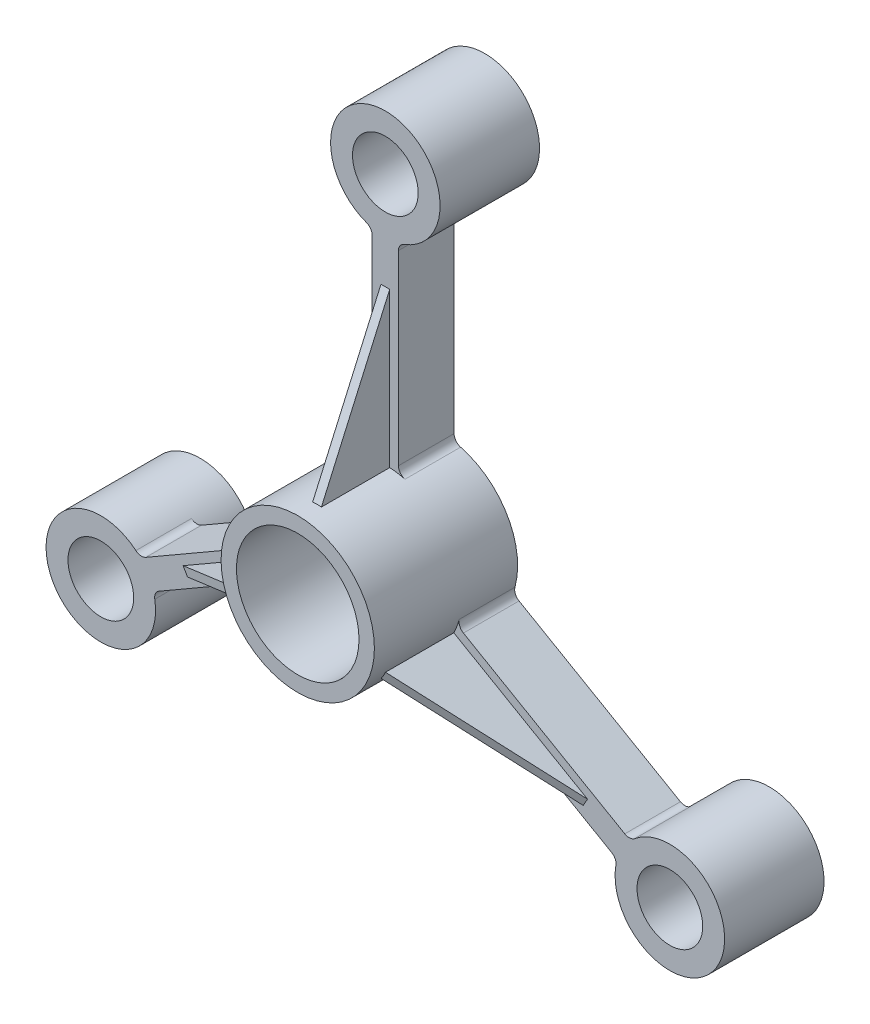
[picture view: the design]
ISO-10303-21;
HEADER;
FILE_DESCRIPTION(('STEP AP214'),'2;1');
FILE_NAME('part.step','',(''),(''),'','','');
FILE_SCHEMA(('AUTOMOTIVE_DESIGN { 1 0 10303 214 1 1 1 1 }'));
ENDSEC;
DATA;
#1=APPLICATION_CONTEXT('core data for automotive mechanical design processes');
#2=APPLICATION_PROTOCOL_DEFINITION('international standard','automotive_design',2000,#1);
#3=PRODUCT_CONTEXT('',#1,'mechanical');
#4=PRODUCT('Part','Part','',(#3));
#5=PRODUCT_RELATED_PRODUCT_CATEGORY('part','',(#4));
#6=PRODUCT_DEFINITION_FORMATION('','',#4);
#7=PRODUCT_DEFINITION_CONTEXT('part definition',#1,'design');
#8=PRODUCT_DEFINITION('design','',#6,#7);
#9=PRODUCT_DEFINITION_SHAPE('','',#8);
#10=(LENGTH_UNIT() NAMED_UNIT(*) SI_UNIT(.MILLI.,.METRE.));
#11=(NAMED_UNIT(*) PLANE_ANGLE_UNIT() SI_UNIT($,.RADIAN.));
#12=(NAMED_UNIT(*) SI_UNIT($,.STERADIAN.) SOLID_ANGLE_UNIT());
#13=UNCERTAINTY_MEASURE_WITH_UNIT(LENGTH_MEASURE(1.E-05),#10,'distance_accuracy_value','');
#14=(GEOMETRIC_REPRESENTATION_CONTEXT(3) GLOBAL_UNCERTAINTY_ASSIGNED_CONTEXT((#13)) GLOBAL_UNIT_ASSIGNED_CONTEXT((#10,
#11,#12)) REPRESENTATION_CONTEXT('',''));
#15=CARTESIAN_POINT('',(0.,0.,0.));
#16=DIRECTION('',(0.,0.,1.));
#17=DIRECTION('',(1.,0.,0.));
#18=AXIS2_PLACEMENT_3D('',#15,#16,#17);
#19=CARTESIAN_POINT('',(5.00000000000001,18.8480768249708,12.7));
#20=DIRECTION('',(0.,0.,1.));
#21=DIRECTION('',(1.,0.,0.));
#22=AXIS2_PLACEMENT_3D('',#19,#20,#21);
#23=PLANE('',#22);
#24=DIRECTION('',(0.,1.,0.));
#25=VECTOR('',#24,1.);
#26=CARTESIAN_POINT('',(1.,18.8480768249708,12.7));
#27=LINE('',#26,#25);
#28=CARTESIAN_POINT('',(1.,17.4714052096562,12.7));
#29=VERTEX_POINT('',#28);
#30=CARTESIAN_POINT('',(1.,52.7236804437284,12.7));
#31=VERTEX_POINT('',#30);
#32=EDGE_CURVE('E306',#29,#31,#27,.T.);
#33=ORIENTED_EDGE('',*,*,#32,.F.);
#34=CARTESIAN_POINT('',(0.,0.,12.7));
#35=DIRECTION('',(0.,0.,1.));
#36=DIRECTION('',(1.,0.,0.));
#37=AXIS2_PLACEMENT_3D('',#34,#35,#36);
#38=CIRCLE('',#37,17.4999999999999);
#39=CARTESIAN_POINT('',(4.48717948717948,16.9149407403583,12.7));
#40=VERTEX_POINT('',#39);
#41=EDGE_CURVE('E349',#40,#29,#38,.T.);
#42=ORIENTED_EDGE('',*,*,#41,.F.);
#43=CARTESIAN_POINT('',(5.00000000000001,18.8480768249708,12.7));
#44=DIRECTION('',(0.,0.,1.));
#45=DIRECTION('',(1.,0.,0.));
#46=AXIS2_PLACEMENT_3D('',#43,#44,#45);
#47=CIRCLE('',#46,2.);
#48=CARTESIAN_POINT('',(3.00000000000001,18.8480768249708,12.7));
#49=VERTEX_POINT('',#48);
#50=EDGE_CURVE('E359',#49,#40,#47,.T.);
#51=ORIENTED_EDGE('',*,*,#50,.F.);
#52=DIRECTION('',(0.,-1.,0.));
#53=VECTOR('',#52,1.);
#54=CARTESIAN_POINT('',(3.,61.3893424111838,12.7));
#55=LINE('',#54,#53);
#56=CARTESIAN_POINT('',(3.,61.3893424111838,12.7));
#57=VERTEX_POINT('',#56);
#58=EDGE_CURVE('E483',#57,#49,#55,.T.);
#59=ORIENTED_EDGE('',*,*,#58,.F.);
#60=CARTESIAN_POINT('',(5.,61.3893424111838,12.7));
#61=DIRECTION('',(0.,0.,1.));
#62=DIRECTION('',(1.,0.,0.));
#63=AXIS2_PLACEMENT_3D('',#60,#61,#62);
#64=CIRCLE('',#63,2.);
#65=CARTESIAN_POINT('',(4.31034482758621,63.2666744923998,12.7));
#66=VERTEX_POINT('',#65);
#67=EDGE_CURVE('E480',#66,#57,#64,.T.);
#68=ORIENTED_EDGE('',*,*,#67,.F.);
#69=CARTESIAN_POINT('',(0.,75.,12.7));
#70=DIRECTION('',(0.,0.,1.));
#71=DIRECTION('',(1.,0.,0.));
#72=AXIS2_PLACEMENT_3D('',#69,#70,#71);
#73=CIRCLE('',#72,12.5);
#74=CARTESIAN_POINT('',(-4.31034482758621,63.2666744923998,12.7));
#75=VERTEX_POINT('',#74);
#76=EDGE_CURVE('E478',#66,#75,#73,.T.);
#77=ORIENTED_EDGE('',*,*,#76,.T.);
#78=CARTESIAN_POINT('',(-5.,61.3893424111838,12.7));
#79=DIRECTION('',(0.,0.,1.));
#80=DIRECTION('',(1.,0.,0.));
#81=AXIS2_PLACEMENT_3D('',#78,#79,#80);
#82=CIRCLE('',#81,1.99999999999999);
#83=CARTESIAN_POINT('',(-3.00000000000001,61.3893424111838,12.7));
#84=VERTEX_POINT('',#83);
#85=EDGE_CURVE('E474',#84,#75,#82,.T.);
#86=ORIENTED_EDGE('',*,*,#85,.F.);
#87=DIRECTION('',(0.,-1.,0.));
#88=VECTOR('',#87,1.);
#89=CARTESIAN_POINT('',(-3.,61.3893424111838,12.7));
#90=LINE('',#89,#88);
#91=CARTESIAN_POINT('',(-3.,18.8480768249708,12.7));
#92=VERTEX_POINT('',#91);
#93=EDGE_CURVE('E472',#84,#92,#90,.T.);
#94=ORIENTED_EDGE('',*,*,#93,.T.);
#95=CARTESIAN_POINT('',(-5.,18.8480768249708,12.7));
#96=DIRECTION('',(0.,0.,1.));
#97=DIRECTION('',(1.,0.,0.));
#98=AXIS2_PLACEMENT_3D('',#95,#96,#97);
#99=CIRCLE('',#98,2.);
#100=CARTESIAN_POINT('',(-4.48717948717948,16.9149407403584,12.7));
#101=VERTEX_POINT('',#100);
#102=EDGE_CURVE('E475',#101,#92,#99,.T.);
#103=ORIENTED_EDGE('',*,*,#102,.F.);
#104=CARTESIAN_POINT('',(-1.,17.4714052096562,12.7));
#105=VERTEX_POINT('',#104);
#106=EDGE_CURVE('E342',#105,#101,#38,.T.);
#107=ORIENTED_EDGE('',*,*,#106,.F.);
#108=DIRECTION('',(0.,1.,0.));
#109=VECTOR('',#108,1.);
#110=CARTESIAN_POINT('',(-1.,18.8480768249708,12.7));
#111=LINE('',#110,#109);
#112=CARTESIAN_POINT('',(-1.,52.7236804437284,12.7));
#113=VERTEX_POINT('',#112);
#114=EDGE_CURVE('E302',#105,#113,#111,.T.);
#115=ORIENTED_EDGE('',*,*,#114,.T.);
#116=DIRECTION('',(-1.,0.,0.));
#117=VECTOR('',#116,1.);
#118=CARTESIAN_POINT('',(5.00000000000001,52.7236804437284,12.7));
#119=LINE('',#118,#117);
#120=EDGE_CURVE('E311',#31,#113,#119,.T.);
#121=ORIENTED_EDGE('',*,*,#120,.F.);
#122=EDGE_LOOP('',(#33,#42,#51,#59,#68,#77,#86,#94,#103,#107,#115,#121));
#123=FACE_BOUND('',#122,.T.);
#124=CARTESIAN_POINT('',(0.,75.,12.7));
#125=DIRECTION('',(0.,0.,1.));
#126=DIRECTION('',(1.,0.,0.));
#127=AXIS2_PLACEMENT_3D('',#124,#125,#126);
#128=CIRCLE('',#127,7.5);
#129=CARTESIAN_POINT('',(7.5,75.,12.7));
#130=VERTEX_POINT('',#129);
#131=EDGE_CURVE('E324',#130,#130,#128,.T.);
#132=ORIENTED_EDGE('',*,*,#131,.F.);
#133=EDGE_LOOP('',(#132));
#134=FACE_BOUND('',#133,.T.);
#135=ADVANCED_FACE('F32',(#123,#134),#23,.T.);
#136=DIRECTION('',(-0.866025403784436,-0.500000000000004,0.));
#137=VECTOR('',#136,1.);
#138=CARTESIAN_POINT('',(11.4114566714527,7.74310811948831,12.7));
#139=LINE('',#138,#137);
#140=CARTESIAN_POINT('',(-15.630680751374,-7.86967720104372,12.7));
#141=VERTEX_POINT('',#140);
#142=CARTESIAN_POINT('',(-46.1600466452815,-25.49581481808,12.7));
#143=VERTEX_POINT('',#142);
#144=EDGE_CURVE('E288',#141,#143,#139,.T.);
#145=ORIENTED_EDGE('',*,*,#144,.F.);
#146=CARTESIAN_POINT('',(-16.8923581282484,-4.57145894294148,12.7));
#147=VERTEX_POINT('',#146);
#148=EDGE_CURVE('E11',#147,#141,#38,.T.);
#149=ORIENTED_EDGE('',*,*,#148,.F.);
#150=CARTESIAN_POINT('',(-18.8229133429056,-5.09391139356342,12.7));
#151=DIRECTION('',(0.,0.,1.));
#152=DIRECTION('',(1.,0.,0.));
#153=AXIS2_PLACEMENT_3D('',#150,#151,#152);
#154=CIRCLE('',#153,2.00000000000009);
#155=CARTESIAN_POINT('',(-17.8229133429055,-6.82596220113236,12.7));
#156=VERTEX_POINT('',#155);
#157=EDGE_CURVE('E471',#156,#147,#154,.T.);
#158=ORIENTED_EDGE('',*,*,#157,.F.);
#159=DIRECTION('',(0.866025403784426,0.500000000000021,0.));
#160=VECTOR('',#159,1.);
#161=CARTESIAN_POINT('',(-54.6647300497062,-28.0965949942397,12.7));
#162=LINE('',#161,#160);
#163=CARTESIAN_POINT('',(-54.6647300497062,-28.0965949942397,12.7));
#164=VERTEX_POINT('',#163);
#165=EDGE_CURVE('E468',#164,#156,#162,.T.);
#166=ORIENTED_EDGE('',*,*,#165,.F.);
#167=CARTESIAN_POINT('',(-55.6647300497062,-26.3645441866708,12.7));
#168=DIRECTION('',(0.,0.,1.));
#169=DIRECTION('',(1.,0.,0.));
#170=AXIS2_PLACEMENT_3D('',#167,#168,#169);
#171=CIRCLE('',#170,2.);
#172=CARTESIAN_POINT('',(-56.9457197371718,-27.9004691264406,12.7));
#173=VERTEX_POINT('',#172);
#174=EDGE_CURVE('E465',#173,#164,#171,.T.);
#175=ORIENTED_EDGE('',*,*,#174,.F.);
#176=CARTESIAN_POINT('',(-64.951905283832,-37.5000000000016,12.7));
#177=DIRECTION('',(0.,0.,1.));
#178=DIRECTION('',(1.,0.,0.));
#179=AXIS2_PLACEMENT_3D('',#176,#177,#178);
#180=CIRCLE('',#179,12.5);
#181=CARTESIAN_POINT('',(-52.6353749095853,-35.3662053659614,12.7));
#182=VERTEX_POINT('',#181);
#183=EDGE_CURVE('E463',#173,#182,#180,.T.);
#184=ORIENTED_EDGE('',*,*,#183,.T.);
#185=CARTESIAN_POINT('',(-50.6647300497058,-35.024798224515,12.7));
#186=DIRECTION('',(0.,0.,-1.));
#187=DIRECTION('',(-1.,0.,0.));
#188=AXIS2_PLACEMENT_3D('',#185,#186,#187);
#189=CIRCLE('',#188,2.);
#190=CARTESIAN_POINT('',(-51.6647300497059,-33.2927474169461,12.7));
#191=VERTEX_POINT('',#190);
#192=EDGE_CURVE('E460',#182,#191,#189,.T.);
#193=ORIENTED_EDGE('',*,*,#192,.T.);
#194=DIRECTION('',(0.866025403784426,0.500000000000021,0.));
#195=VECTOR('',#194,1.);
#196=CARTESIAN_POINT('',(-51.6647300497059,-33.2927474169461,12.7));
#197=LINE('',#196,#195);
#198=CARTESIAN_POINT('',(-14.8229133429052,-12.0221146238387,12.7));
#199=VERTEX_POINT('',#198);
#200=EDGE_CURVE('E458',#191,#199,#197,.T.);
#201=ORIENTED_EDGE('',*,*,#200,.T.);
#202=CARTESIAN_POINT('',(-13.8229133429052,-13.7541654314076,12.7));
#203=DIRECTION('',(0.,0.,-1.));
#204=DIRECTION('',(-1.,0.,0.));
#205=AXIS2_PLACEMENT_3D('',#202,#203,#204);
#206=CIRCLE('',#205,1.99999999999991);
#207=CARTESIAN_POINT('',(-12.4051786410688,-12.3434817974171,12.7));
#208=VERTEX_POINT('',#207);
#209=EDGE_CURVE('E461',#199,#208,#206,.T.);
#210=ORIENTED_EDGE('',*,*,#209,.T.);
#211=CARTESIAN_POINT('',(-14.630680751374,-9.60172800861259,12.7));
#212=VERTEX_POINT('',#211);
#213=EDGE_CURVE('E42',#212,#208,#38,.T.);
#214=ORIENTED_EDGE('',*,*,#213,.F.);
#215=DIRECTION('',(-0.866025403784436,-0.500000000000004,0.));
#216=VECTOR('',#215,1.);
#217=CARTESIAN_POINT('',(12.4114566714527,6.01105731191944,12.7));
#218=LINE('',#217,#216);
#219=CARTESIAN_POINT('',(-45.1600466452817,-27.227865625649,12.6999999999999));
#220=VERTEX_POINT('',#219);
#221=EDGE_CURVE('E284',#212,#220,#218,.T.);
#222=ORIENTED_EDGE('',*,*,#221,.T.);
#223=DIRECTION('',(0.500000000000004,-0.866025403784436,0.));
#224=VECTOR('',#223,1.);
#225=CARTESIAN_POINT('',(-52.5715033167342,-14.3908461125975,12.7));
#226=LINE('',#225,#224);
#227=EDGE_CURVE('E58',#143,#220,#226,.T.);
#228=ORIENTED_EDGE('',*,*,#227,.F.);
#229=EDGE_LOOP('',(#145,#149,#158,#166,#175,#184,#193,#201,#210,#214,#222,#228));
#230=FACE_BOUND('',#229,.T.);
#231=CARTESIAN_POINT('',(-64.951905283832,-37.5000000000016,12.7));
#232=DIRECTION('',(0.,0.,1.));
#233=DIRECTION('',(1.,0.,0.));
#234=AXIS2_PLACEMENT_3D('',#231,#232,#233);
#235=CIRCLE('',#234,7.5);
#236=CARTESIAN_POINT('',(-57.451905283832,-37.5000000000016,12.7));
#237=VERTEX_POINT('',#236);
#238=EDGE_CURVE('E318',#237,#237,#235,.T.);
#239=ORIENTED_EDGE('',*,*,#238,.F.);
#240=EDGE_LOOP('',(#239));
#241=FACE_BOUND('',#240,.T.);
#242=ADVANCED_FACE('F624',(#230,#241),#23,.T.);
#243=CARTESIAN_POINT('',(5.00000000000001,18.8480768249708,0.));
#244=DIRECTION('',(0.,0.,1.));
#245=DIRECTION('',(1.,0.,0.));
#246=AXIS2_PLACEMENT_3D('',#243,#244,#245);
#247=PLANE('',#246);
#248=CARTESIAN_POINT('',(0.,0.,0.));
#249=DIRECTION('',(0.,0.,1.));
#250=DIRECTION('',(1.,0.,0.));
#251=AXIS2_PLACEMENT_3D('',#248,#249,#250);
#252=CIRCLE('',#251,8.33292396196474);
#253=CARTESIAN_POINT('',(8.33292396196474,0.,0.));
#254=VERTEX_POINT('',#253);
#255=EDGE_CURVE('E335',#254,#254,#252,.T.);
#256=ORIENTED_EDGE('',*,*,#255,.T.);
#257=EDGE_LOOP('',(#256));
#258=FACE_BOUND('',#257,.T.);
#259=CARTESIAN_POINT('',(-18.8229133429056,-5.09391139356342,0.));
#260=DIRECTION('',(0.,0.,1.));
#261=DIRECTION('',(1.,0.,0.));
#262=AXIS2_PLACEMENT_3D('',#259,#260,#261);
#263=CIRCLE('',#262,2.00000000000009);
#264=CARTESIAN_POINT('',(-17.8229133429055,-6.82596220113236,0.));
#265=VERTEX_POINT('',#264);
#266=CARTESIAN_POINT('',(-16.8923581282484,-4.57145894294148,0.));
#267=VERTEX_POINT('',#266);
#268=EDGE_CURVE('E522',#265,#267,#263,.T.);
#269=ORIENTED_EDGE('',*,*,#268,.T.);
#270=CARTESIAN_POINT('',(0.,0.,0.));
#271=DIRECTION('',(0.,0.,1.));
#272=DIRECTION('',(1.,0.,0.));
#273=AXIS2_PLACEMENT_3D('',#270,#271,#272);
#274=CIRCLE('',#273,17.5);
#275=CARTESIAN_POINT('',(-4.48717948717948,16.9149407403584,0.));
#276=VERTEX_POINT('',#275);
#277=EDGE_CURVE('E525',#276,#267,#274,.T.);
#278=ORIENTED_EDGE('',*,*,#277,.F.);
#279=CARTESIAN_POINT('',(-5.,18.8480768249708,0.));
#280=DIRECTION('',(0.,0.,1.));
#281=DIRECTION('',(1.,0.,0.));
#282=AXIS2_PLACEMENT_3D('',#279,#280,#281);
#283=CIRCLE('',#282,2.);
#284=CARTESIAN_POINT('',(-3.,18.8480768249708,0.));
#285=VERTEX_POINT('',#284);
#286=EDGE_CURVE('E527',#276,#285,#283,.T.);
#287=ORIENTED_EDGE('',*,*,#286,.T.);
#288=DIRECTION('',(0.,-1.,0.));
#289=VECTOR('',#288,1.);
#290=CARTESIAN_POINT('',(-3.,61.3893424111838,0.));
#291=LINE('',#290,#289);
#292=CARTESIAN_POINT('',(-3.00000000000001,61.3893424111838,0.));
#293=VERTEX_POINT('',#292);
#294=EDGE_CURVE('E529',#293,#285,#291,.T.);
#295=ORIENTED_EDGE('',*,*,#294,.F.);
#296=CARTESIAN_POINT('',(-5.,61.3893424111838,0.));
#297=DIRECTION('',(0.,0.,1.));
#298=DIRECTION('',(1.,0.,0.));
#299=AXIS2_PLACEMENT_3D('',#296,#297,#298);
#300=CIRCLE('',#299,1.99999999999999);
#301=CARTESIAN_POINT('',(-4.31034482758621,63.2666744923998,0.));
#302=VERTEX_POINT('',#301);
#303=EDGE_CURVE('E531',#293,#302,#300,.T.);
#304=ORIENTED_EDGE('',*,*,#303,.T.);
#305=CARTESIAN_POINT('',(0.,75.,0.));
#306=DIRECTION('',(0.,0.,-1.));
#307=DIRECTION('',(-1.,0.,0.));
#308=AXIS2_PLACEMENT_3D('',#305,#306,#307);
#309=CIRCLE('',#308,12.5);
#310=CARTESIAN_POINT('',(4.3103448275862,63.2666744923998,0.));
#311=VERTEX_POINT('',#310);
#312=EDGE_CURVE('E437',#311,#302,#309,.T.);
#313=ORIENTED_EDGE('',*,*,#312,.F.);
#314=CARTESIAN_POINT('',(5.,61.3893424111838,0.));
#315=DIRECTION('',(0.,0.,1.));
#316=DIRECTION('',(1.,0.,0.));
#317=AXIS2_PLACEMENT_3D('',#314,#315,#316);
#318=CIRCLE('',#317,2.);
#319=CARTESIAN_POINT('',(3.,61.3893424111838,0.));
#320=VERTEX_POINT('',#319);
#321=EDGE_CURVE('E536',#311,#320,#318,.T.);
#322=ORIENTED_EDGE('',*,*,#321,.T.);
#323=DIRECTION('',(0.,-1.,0.));
#324=VECTOR('',#323,1.);
#325=CARTESIAN_POINT('',(3.,61.3893424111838,0.));
#326=LINE('',#325,#324);
#327=CARTESIAN_POINT('',(3.00000000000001,18.8480768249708,0.));
#328=VERTEX_POINT('',#327);
#329=EDGE_CURVE('E389',#320,#328,#326,.T.);
#330=ORIENTED_EDGE('',*,*,#329,.T.);
#331=CARTESIAN_POINT('',(5.00000000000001,18.8480768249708,0.));
#332=DIRECTION('',(0.,0.,1.));
#333=DIRECTION('',(1.,0.,0.));
#334=AXIS2_PLACEMENT_3D('',#331,#332,#333);
#335=CIRCLE('',#334,2.);
#336=CARTESIAN_POINT('',(4.48717948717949,16.9149407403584,0.));
#337=VERTEX_POINT('',#336);
#338=EDGE_CURVE('E486',#328,#337,#335,.T.);
#339=ORIENTED_EDGE('',*,*,#338,.T.);
#340=CARTESIAN_POINT('',(0.,0.,0.));
#341=DIRECTION('',(0.,0.,1.));
#342=DIRECTION('',(1.,0.,0.));
#343=AXIS2_PLACEMENT_3D('',#340,#341,#342);
#344=CIRCLE('',#343,17.5);
#345=CARTESIAN_POINT('',(16.8923581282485,-4.57145894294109,0.));
#346=VERTEX_POINT('',#345);
#347=EDGE_CURVE('E489',#346,#337,#344,.T.);
#348=ORIENTED_EDGE('',*,*,#347,.F.);
#349=CARTESIAN_POINT('',(18.8229133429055,-5.09391139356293,0.));
#350=DIRECTION('',(0.,0.,1.));
#351=DIRECTION('',(1.,0.,0.));
#352=AXIS2_PLACEMENT_3D('',#349,#350,#351);
#353=CIRCLE('',#352,2.);
#354=CARTESIAN_POINT('',(17.8229133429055,-6.82596220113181,0.));
#355=VERTEX_POINT('',#354);
#356=EDGE_CURVE('E491',#346,#355,#353,.T.);
#357=ORIENTED_EDGE('',*,*,#356,.T.);
#358=DIRECTION('',(0.866025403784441,-0.499999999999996,0.));
#359=VECTOR('',#358,1.);
#360=CARTESIAN_POINT('',(17.8229133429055,-6.82596220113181,0.));
#361=LINE('',#360,#359);
#362=CARTESIAN_POINT('',(54.6647300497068,-28.0965949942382,0.));
#363=VERTEX_POINT('',#362);
#364=EDGE_CURVE('E494',#355,#363,#361,.T.);
#365=ORIENTED_EDGE('',*,*,#364,.T.);
#366=CARTESIAN_POINT('',(55.6647300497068,-26.3645441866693,0.));
#367=DIRECTION('',(0.,0.,1.));
#368=DIRECTION('',(1.,0.,0.));
#369=AXIS2_PLACEMENT_3D('',#366,#367,#368);
#370=CIRCLE('',#369,2.00000000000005);
#371=CARTESIAN_POINT('',(56.9457197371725,-27.9004691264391,0.));
#372=VERTEX_POINT('',#371);
#373=EDGE_CURVE('E497',#363,#372,#370,.T.);
#374=ORIENTED_EDGE('',*,*,#373,.T.);
#375=CARTESIAN_POINT('',(64.9519052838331,-37.4999999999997,0.));
#376=DIRECTION('',(0.,0.,-1.));
#377=DIRECTION('',(-1.,0.,0.));
#378=AXIS2_PLACEMENT_3D('',#375,#376,#377);
#379=CIRCLE('',#378,12.5);
#380=CARTESIAN_POINT('',(52.6353749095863,-35.3662053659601,0.));
#381=VERTEX_POINT('',#380);
#382=EDGE_CURVE('E696',#381,#372,#379,.T.);
#383=ORIENTED_EDGE('',*,*,#382,.F.);
#384=CARTESIAN_POINT('',(50.6647300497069,-35.0247982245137,0.));
#385=DIRECTION('',(0.,0.,1.));
#386=DIRECTION('',(1.,0.,0.));
#387=AXIS2_PLACEMENT_3D('',#384,#385,#386);
#388=CIRCLE('',#387,1.99999999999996);
#389=CARTESIAN_POINT('',(51.6647300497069,-33.2927474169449,0.));
#390=VERTEX_POINT('',#389);
#391=EDGE_CURVE('E500',#381,#390,#388,.T.);
#392=ORIENTED_EDGE('',*,*,#391,.T.);
#393=DIRECTION('',(0.866025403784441,-0.499999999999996,0.));
#394=VECTOR('',#393,1.);
#395=CARTESIAN_POINT('',(14.8229133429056,-12.0221146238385,0.));
#396=LINE('',#395,#394);
#397=CARTESIAN_POINT('',(14.8229133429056,-12.0221146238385,0.));
#398=VERTEX_POINT('',#397);
#399=EDGE_CURVE('E503',#398,#390,#396,.T.);
#400=ORIENTED_EDGE('',*,*,#399,.F.);
#401=CARTESIAN_POINT('',(13.8229133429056,-13.7541654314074,0.));
#402=DIRECTION('',(0.,0.,-1.));
#403=DIRECTION('',(-1.,0.,0.));
#404=AXIS2_PLACEMENT_3D('',#401,#402,#403);
#405=CIRCLE('',#404,2.);
#406=CARTESIAN_POINT('',(12.4051786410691,-12.3434817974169,0.));
#407=VERTEX_POINT('',#406);
#408=EDGE_CURVE('E506',#407,#398,#405,.T.);
#409=ORIENTED_EDGE('',*,*,#408,.F.);
#410=CARTESIAN_POINT('',(0.,0.,0.));
#411=DIRECTION('',(0.,0.,1.));
#412=DIRECTION('',(1.,0.,0.));
#413=AXIS2_PLACEMENT_3D('',#410,#411,#412);
#414=CIRCLE('',#413,17.5);
#415=CARTESIAN_POINT('',(-12.4051786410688,-12.3434817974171,0.));
#416=VERTEX_POINT('',#415);
#417=EDGE_CURVE('E508',#416,#407,#414,.T.);
#418=ORIENTED_EDGE('',*,*,#417,.F.);
#419=CARTESIAN_POINT('',(-13.8229133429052,-13.7541654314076,0.));
#420=DIRECTION('',(0.,0.,-1.));
#421=DIRECTION('',(-1.,0.,0.));
#422=AXIS2_PLACEMENT_3D('',#419,#420,#421);
#423=CIRCLE('',#422,1.99999999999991);
#424=CARTESIAN_POINT('',(-14.8229133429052,-12.0221146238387,0.));
#425=VERTEX_POINT('',#424);
#426=EDGE_CURVE('E510',#425,#416,#423,.T.);
#427=ORIENTED_EDGE('',*,*,#426,.F.);
#428=DIRECTION('',(0.866025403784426,0.500000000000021,0.));
#429=VECTOR('',#428,1.);
#430=CARTESIAN_POINT('',(-51.6647300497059,-33.2927474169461,0.));
#431=LINE('',#430,#429);
#432=CARTESIAN_POINT('',(-51.6647300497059,-33.2927474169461,0.));
#433=VERTEX_POINT('',#432);
#434=EDGE_CURVE('E512',#433,#425,#431,.T.);
#435=ORIENTED_EDGE('',*,*,#434,.F.);
#436=CARTESIAN_POINT('',(-50.6647300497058,-35.024798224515,0.));
#437=DIRECTION('',(0.,0.,-1.));
#438=DIRECTION('',(-1.,0.,0.));
#439=AXIS2_PLACEMENT_3D('',#436,#437,#438);
#440=CIRCLE('',#439,2.);
#441=CARTESIAN_POINT('',(-52.6353749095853,-35.3662053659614,0.));
#442=VERTEX_POINT('',#441);
#443=EDGE_CURVE('E514',#442,#433,#440,.T.);
#444=ORIENTED_EDGE('',*,*,#443,.F.);
#445=CARTESIAN_POINT('',(-64.951905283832,-37.5000000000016,0.));
#446=DIRECTION('',(0.,0.,-1.));
#447=DIRECTION('',(-1.,0.,0.));
#448=AXIS2_PLACEMENT_3D('',#445,#446,#447);
#449=CIRCLE('',#448,12.5);
#450=CARTESIAN_POINT('',(-56.9457197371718,-27.9004691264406,0.));
#451=VERTEX_POINT('',#450);
#452=EDGE_CURVE('E348',#451,#442,#449,.T.);
#453=ORIENTED_EDGE('',*,*,#452,.F.);
#454=CARTESIAN_POINT('',(-55.6647300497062,-26.3645441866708,0.));
#455=DIRECTION('',(0.,0.,1.));
#456=DIRECTION('',(1.,0.,0.));
#457=AXIS2_PLACEMENT_3D('',#454,#455,#456);
#458=CIRCLE('',#457,2.);
#459=CARTESIAN_POINT('',(-54.6647300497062,-28.0965949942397,0.));
#460=VERTEX_POINT('',#459);
#461=EDGE_CURVE('E516',#451,#460,#458,.T.);
#462=ORIENTED_EDGE('',*,*,#461,.T.);
#463=DIRECTION('',(0.866025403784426,0.500000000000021,0.));
#464=VECTOR('',#463,1.);
#465=CARTESIAN_POINT('',(-54.6647300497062,-28.0965949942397,0.));
#466=LINE('',#465,#464);
#467=EDGE_CURVE('E519',#460,#265,#466,.T.);
#468=ORIENTED_EDGE('',*,*,#467,.T.);
#469=EDGE_LOOP('',(#269,#278,#287,#295,#304,#313,#322,#330,#339,#348,#357,#365,#374,#383,#392,
#400,#409,#418,#427,#435,#444,#453,#462,#468));
#470=FACE_BOUND('',#469,.T.);
#471=ADVANCED_FACE('F558',(#258,#470),#247,.F.);
#472=CARTESIAN_POINT('',(5.00000000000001,18.8480768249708,12.7));
#473=DIRECTION('',(0.,0.,-1.));
#474=DIRECTION('',(-1.,0.,0.));
#475=AXIS2_PLACEMENT_3D('',#472,#473,#474);
#476=CYLINDRICAL_SURFACE('',#475,2.);
#477=ORIENTED_EDGE('',*,*,#338,.F.);
#478=DIRECTION('',(0.,0.,-1.));
#479=VECTOR('',#478,1.);
#480=CARTESIAN_POINT('',(3.00000000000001,18.8480768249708,12.7));
#481=LINE('',#480,#479);
#482=EDGE_CURVE('E378',#49,#328,#481,.T.);
#483=ORIENTED_EDGE('',*,*,#482,.F.);
#484=ORIENTED_EDGE('',*,*,#50,.T.);
#485=DIRECTION('',(0.,0.,-1.));
#486=VECTOR('',#485,1.);
#487=CARTESIAN_POINT('',(4.48717948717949,16.9149407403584,12.7));
#488=LINE('',#487,#486);
#489=EDGE_CURVE('E485',#40,#337,#488,.T.);
#490=ORIENTED_EDGE('',*,*,#489,.T.);
#491=EDGE_LOOP('',(#477,#483,#484,#490));
#492=FACE_BOUND('',#491,.T.);
#493=ADVANCED_FACE('F34',(#492),#476,.F.);
#494=CARTESIAN_POINT('',(3.,61.3893424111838,12.7));
#495=DIRECTION('',(1.,0.,0.));
#496=DIRECTION('',(0.,1.,0.));
#497=AXIS2_PLACEMENT_3D('',#494,#495,#496);
#498=PLANE('',#497);
#499=ORIENTED_EDGE('',*,*,#329,.F.);
#500=DIRECTION('',(0.,0.,-1.));
#501=VECTOR('',#500,1.);
#502=CARTESIAN_POINT('',(3.,61.3893424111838,12.7));
#503=LINE('',#502,#501);
#504=EDGE_CURVE('E380',#57,#320,#503,.T.);
#505=ORIENTED_EDGE('',*,*,#504,.F.);
#506=ORIENTED_EDGE('',*,*,#58,.T.);
#507=ORIENTED_EDGE('',*,*,#482,.T.);
#508=EDGE_LOOP('',(#499,#505,#506,#507));
#509=FACE_BOUND('',#508,.T.);
#510=ADVANCED_FACE('F561',(#509),#498,.T.);
#511=CARTESIAN_POINT('',(5.,61.3893424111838,12.7));
#512=DIRECTION('',(0.,0.,-1.));
#513=DIRECTION('',(-1.,0.,0.));
#514=AXIS2_PLACEMENT_3D('',#511,#512,#513);
#515=CYLINDRICAL_SURFACE('',#514,2.);
#516=ORIENTED_EDGE('',*,*,#321,.F.);
#517=DIRECTION('',(0.,0.,-1.));
#518=VECTOR('',#517,1.);
#519=CARTESIAN_POINT('',(4.31034482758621,63.2666744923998,12.7));
#520=LINE('',#519,#518);
#521=EDGE_CURVE('E386',#66,#311,#520,.T.);
#522=ORIENTED_EDGE('',*,*,#521,.F.);
#523=ORIENTED_EDGE('',*,*,#67,.T.);
#524=ORIENTED_EDGE('',*,*,#504,.T.);
#525=EDGE_LOOP('',(#516,#522,#523,#524));
#526=FACE_BOUND('',#525,.T.);
#527=ADVANCED_FACE('F797',(#526),#515,.F.);
#528=CARTESIAN_POINT('',(0.,75.,12.7));
#529=DIRECTION('',(0.,0.,-1.));
#530=DIRECTION('',(-1.,0.,0.));
#531=AXIS2_PLACEMENT_3D('',#528,#529,#530);
#532=CYLINDRICAL_SURFACE('',#531,12.5);
#533=CARTESIAN_POINT('',(0.,75.,-10.));
#534=DIRECTION('',(0.,0.,-1.));
#535=DIRECTION('',(-1.,0.,0.));
#536=AXIS2_PLACEMENT_3D('',#533,#534,#535);
#537=CIRCLE('',#536,12.5);
#538=CARTESIAN_POINT('',(-12.5,75.,-10.));
#539=VERTEX_POINT('',#538);
#540=EDGE_CURVE('E440',#539,#539,#537,.T.);
#541=ORIENTED_EDGE('',*,*,#540,.F.);
#542=EDGE_LOOP('',(#541));
#543=FACE_BOUND('',#542,.T.);
#544=ORIENTED_EDGE('',*,*,#312,.T.);
#545=DIRECTION('',(0.,0.,-1.));
#546=VECTOR('',#545,1.);
#547=CARTESIAN_POINT('',(-4.31034482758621,63.2666744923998,12.7));
#548=LINE('',#547,#546);
#549=EDGE_CURVE('E394',#75,#302,#548,.T.);
#550=ORIENTED_EDGE('',*,*,#549,.F.);
#551=ORIENTED_EDGE('',*,*,#76,.F.);
#552=ORIENTED_EDGE('',*,*,#521,.T.);
#553=EDGE_LOOP('',(#544,#550,#551,#552));
#554=FACE_BOUND('',#553,.T.);
#555=ADVANCED_FACE('F556',(#543,#554),#532,.T.);
#556=CARTESIAN_POINT('',(-5.,61.3893424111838,12.7));
#557=DIRECTION('',(0.,0.,-1.));
#558=DIRECTION('',(-1.,0.,0.));
#559=AXIS2_PLACEMENT_3D('',#556,#557,#558);
#560=CYLINDRICAL_SURFACE('',#559,1.99999999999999);
#561=ORIENTED_EDGE('',*,*,#303,.F.);
#562=DIRECTION('',(0.,0.,-1.));
#563=VECTOR('',#562,1.);
#564=CARTESIAN_POINT('',(-3.00000000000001,61.3893424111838,12.7));
#565=LINE('',#564,#563);
#566=EDGE_CURVE('E392',#84,#293,#565,.T.);
#567=ORIENTED_EDGE('',*,*,#566,.F.);
#568=ORIENTED_EDGE('',*,*,#85,.T.);
#569=ORIENTED_EDGE('',*,*,#549,.T.);
#570=EDGE_LOOP('',(#561,#567,#568,#569));
#571=FACE_BOUND('',#570,.T.);
#572=ADVANCED_FACE('F554',(#571),#560,.F.);
#573=CARTESIAN_POINT('',(-3.,61.3893424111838,12.7));
#574=DIRECTION('',(1.,0.,0.));
#575=DIRECTION('',(0.,1.,0.));
#576=AXIS2_PLACEMENT_3D('',#573,#574,#575);
#577=PLANE('',#576);
#578=ORIENTED_EDGE('',*,*,#294,.T.);
#579=DIRECTION('',(0.,0.,-1.));
#580=VECTOR('',#579,1.);
#581=CARTESIAN_POINT('',(-3.,18.8480768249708,12.7));
#582=LINE('',#581,#580);
#583=EDGE_CURVE('E395',#92,#285,#582,.T.);
#584=ORIENTED_EDGE('',*,*,#583,.F.);
#585=ORIENTED_EDGE('',*,*,#93,.F.);
#586=ORIENTED_EDGE('',*,*,#566,.T.);
#587=EDGE_LOOP('',(#578,#584,#585,#586));
#588=FACE_BOUND('',#587,.T.);
#589=ADVANCED_FACE('F614',(#588),#577,.F.);
#590=CARTESIAN_POINT('',(-5.,18.8480768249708,12.7));
#591=DIRECTION('',(0.,0.,-1.));
#592=DIRECTION('',(-1.,0.,0.));
#593=AXIS2_PLACEMENT_3D('',#590,#591,#592);
#594=CYLINDRICAL_SURFACE('',#593,2.);
#595=ORIENTED_EDGE('',*,*,#286,.F.);
#596=DIRECTION('',(0.,0.,-1.));
#597=VECTOR('',#596,1.);
#598=CARTESIAN_POINT('',(-4.48717948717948,16.9149407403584,12.7));
#599=LINE('',#598,#597);
#600=EDGE_CURVE('E397',#101,#276,#599,.T.);
#601=ORIENTED_EDGE('',*,*,#600,.F.);
#602=ORIENTED_EDGE('',*,*,#102,.T.);
#603=ORIENTED_EDGE('',*,*,#583,.T.);
#604=EDGE_LOOP('',(#595,#601,#602,#603));
#605=FACE_BOUND('',#604,.T.);
#606=ADVANCED_FACE('F608',(#605),#594,.F.);
#607=CARTESIAN_POINT('',(0.,0.,12.7));
#608=DIRECTION('',(0.,0.,-1.));
#609=DIRECTION('',(-1.,0.,0.));
#610=AXIS2_PLACEMENT_3D('',#607,#608,#609);
#611=CYLINDRICAL_SURFACE('',#610,17.5);
#612=ORIENTED_EDGE('',*,*,#277,.T.);
#613=DIRECTION('',(0.,0.,-1.));
#614=VECTOR('',#613,1.);
#615=CARTESIAN_POINT('',(-16.8923581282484,-4.57145894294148,12.7));
#616=LINE('',#615,#614);
#617=EDGE_CURVE('E400',#147,#267,#616,.T.);
#618=ORIENTED_EDGE('',*,*,#617,.F.);
#619=ORIENTED_EDGE('',*,*,#148,.T.);
#620=DIRECTION('',(0.,0.,-1.));
#621=VECTOR('',#620,1.);
#622=CARTESIAN_POINT('',(-15.630680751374,-7.86967720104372,12.7));
#623=LINE('',#622,#621);
#624=CARTESIAN_POINT('',(-15.630680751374,-7.86967720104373,28.2923525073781));
#625=VERTEX_POINT('',#624);
#626=EDGE_CURVE('E286',#141,#625,#623,.F.);
#627=ORIENTED_EDGE('',*,*,#626,.T.);
#628=CARTESIAN_POINT('',(0.,0.,36.0200894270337));
#629=DIRECTION('',(-0.350312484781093,-0.202253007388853,0.914535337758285));
#630=DIRECTION('',(-0.792010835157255,-0.457267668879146,-0.404506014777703));
#631=AXIS2_PLACEMENT_3D('',#628,#629,#630);
#632=ELLIPSE('',#631,19.1354005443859,17.5);
#633=CARTESIAN_POINT('',(-14.630680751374,-9.60172800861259,28.2923525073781));
#634=VERTEX_POINT('',#633);
#635=EDGE_CURVE('E290',#625,#634,#632,.T.);
#636=ORIENTED_EDGE('',*,*,#635,.T.);
#637=DIRECTION('',(0.,0.,-1.));
#638=VECTOR('',#637,1.);
#639=CARTESIAN_POINT('',(-14.630680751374,-9.60172800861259,12.7));
#640=LINE('',#639,#638);
#641=EDGE_CURVE('E280',#212,#634,#640,.F.);
#642=ORIENTED_EDGE('',*,*,#641,.F.);
#643=ORIENTED_EDGE('',*,*,#213,.T.);
#644=DIRECTION('',(0.,0.,-1.));
#645=VECTOR('',#644,1.);
#646=CARTESIAN_POINT('',(-12.4051786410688,-12.3434817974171,12.7));
#647=LINE('',#646,#645);
#648=EDGE_CURVE('E415',#208,#416,#647,.T.);
#649=ORIENTED_EDGE('',*,*,#648,.T.);
#650=ORIENTED_EDGE('',*,*,#417,.T.);
#651=DIRECTION('',(0.,0.,-1.));
#652=VECTOR('',#651,1.);
#653=CARTESIAN_POINT('',(12.4051786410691,-12.3434817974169,12.7));
#654=LINE('',#653,#652);
#655=CARTESIAN_POINT('',(12.4051786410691,-12.3434817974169,12.7));
#656=VERTEX_POINT('',#655);
#657=EDGE_CURVE('E419',#656,#407,#654,.T.);
#658=ORIENTED_EDGE('',*,*,#657,.F.);
#659=CARTESIAN_POINT('',(14.6306807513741,-9.60172800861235,12.7));
#660=VERTEX_POINT('',#659);
#661=EDGE_CURVE('E366',#656,#660,#38,.T.);
#662=ORIENTED_EDGE('',*,*,#661,.T.);
#663=DIRECTION('',(0.,0.,-1.));
#664=VECTOR('',#663,1.);
#665=CARTESIAN_POINT('',(14.6306807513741,-9.60172800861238,12.7));
#666=LINE('',#665,#664);
#667=CARTESIAN_POINT('',(14.6306807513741,-9.60172800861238,28.2923525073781));
#668=VERTEX_POINT('',#667);
#669=EDGE_CURVE('E270',#660,#668,#666,.F.);
#670=ORIENTED_EDGE('',*,*,#669,.T.);
#671=CARTESIAN_POINT('',(0.,0.,36.0200894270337));
#672=DIRECTION('',(0.350312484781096,-0.202253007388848,0.914535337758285));
#673=DIRECTION('',(0.792010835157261,-0.457267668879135,-0.404506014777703));
#674=AXIS2_PLACEMENT_3D('',#671,#672,#673);
#675=ELLIPSE('',#674,19.1354005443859,17.5);
#676=CARTESIAN_POINT('',(15.6306807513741,-7.8696772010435,28.2923525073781));
#677=VERTEX_POINT('',#676);
#678=EDGE_CURVE('E260',#668,#677,#675,.T.);
#679=ORIENTED_EDGE('',*,*,#678,.T.);
#680=DIRECTION('',(0.,0.,-1.));
#681=VECTOR('',#680,1.);
#682=CARTESIAN_POINT('',(15.6306807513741,-7.8696772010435,12.7));
#683=LINE('',#682,#681);
#684=CARTESIAN_POINT('',(15.630680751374,-7.86967720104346,12.7));
#685=VERTEX_POINT('',#684);
#686=EDGE_CURVE('E248',#685,#677,#683,.F.);
#687=ORIENTED_EDGE('',*,*,#686,.F.);
#688=CARTESIAN_POINT('',(16.8923581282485,-4.57145894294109,12.7));
#689=VERTEX_POINT('',#688);
#690=EDGE_CURVE('E36',#685,#689,#38,.T.);
#691=ORIENTED_EDGE('',*,*,#690,.T.);
#692=DIRECTION('',(0.,0.,-1.));
#693=VECTOR('',#692,1.);
#694=CARTESIAN_POINT('',(16.8923581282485,-4.57145894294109,12.7));
#695=LINE('',#694,#693);
#696=EDGE_CURVE('E432',#689,#346,#695,.T.);
#697=ORIENTED_EDGE('',*,*,#696,.T.);
#698=ORIENTED_EDGE('',*,*,#347,.T.);
#699=ORIENTED_EDGE('',*,*,#489,.F.);
#700=ORIENTED_EDGE('',*,*,#41,.T.);
#701=DIRECTION('',(0.,0.,-1.));
#702=VECTOR('',#701,1.);
#703=CARTESIAN_POINT('',(1.,17.4714052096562,12.7));
#704=LINE('',#703,#702);
#705=CARTESIAN_POINT('',(1.,17.4714052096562,28.2923525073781));
#706=VERTEX_POINT('',#705);
#707=EDGE_CURVE('E304',#29,#706,#704,.F.);
#708=ORIENTED_EDGE('',*,*,#707,.T.);
#709=CARTESIAN_POINT('',(0.,0.,36.0200894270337));
#710=DIRECTION('',(0.,0.404506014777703,0.914535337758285));
#711=DIRECTION('',(0.,0.914535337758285,-0.404506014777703));
#712=AXIS2_PLACEMENT_3D('',#709,#710,#711);
#713=ELLIPSE('',#712,19.1354005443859,17.5);
#714=CARTESIAN_POINT('',(-1.,17.4714052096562,28.2923525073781));
#715=VERTEX_POINT('',#714);
#716=EDGE_CURVE('E309',#706,#715,#713,.T.);
#717=ORIENTED_EDGE('',*,*,#716,.T.);
#718=DIRECTION('',(0.,0.,-1.));
#719=VECTOR('',#718,1.);
#720=CARTESIAN_POINT('',(-1.,17.4714052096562,12.7));
#721=LINE('',#720,#719);
#722=EDGE_CURVE('E297',#105,#715,#721,.F.);
#723=ORIENTED_EDGE('',*,*,#722,.F.);
#724=ORIENTED_EDGE('',*,*,#106,.T.);
#725=ORIENTED_EDGE('',*,*,#600,.T.);
#726=EDGE_LOOP('',(#612,#618,#619,#627,#636,#642,#643,#649,#650,#658,#662,#670,#679,#687,#691,
#697,#698,#699,#700,#708,#717,#723,#724,#725));
#727=FACE_BOUND('',#726,.T.);
#728=CARTESIAN_POINT('',(0.,0.,32.7));
#729=DIRECTION('',(0.,0.,1.));
#730=DIRECTION('',(1.,0.,0.));
#731=AXIS2_PLACEMENT_3D('',#728,#729,#730);
#732=CIRCLE('',#731,17.4999999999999);
#733=CARTESIAN_POINT('',(17.4999999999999,0.,32.7));
#734=VERTEX_POINT('',#733);
#735=EDGE_CURVE('E345',#734,#734,#732,.T.);
#736=ORIENTED_EDGE('',*,*,#735,.F.);
#737=EDGE_LOOP('',(#736));
#738=FACE_BOUND('',#737,.T.);
#739=ADVANCED_FACE('F267',(#727,#738),#611,.T.);
#740=CARTESIAN_POINT('',(-18.8229133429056,-5.09391139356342,12.7));
#741=DIRECTION('',(0.,0.,-1.));
#742=DIRECTION('',(-1.,0.,0.));
#743=AXIS2_PLACEMENT_3D('',#740,#741,#742);
#744=CYLINDRICAL_SURFACE('',#743,2.00000000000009);
#745=ORIENTED_EDGE('',*,*,#268,.F.);
#746=DIRECTION('',(0.,0.,-1.));
#747=VECTOR('',#746,1.);
#748=CARTESIAN_POINT('',(-17.8229133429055,-6.82596220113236,12.7));
#749=LINE('',#748,#747);
#750=EDGE_CURVE('E398',#156,#265,#749,.T.);
#751=ORIENTED_EDGE('',*,*,#750,.F.);
#752=ORIENTED_EDGE('',*,*,#157,.T.);
#753=ORIENTED_EDGE('',*,*,#617,.T.);
#754=EDGE_LOOP('',(#745,#751,#752,#753));
#755=FACE_BOUND('',#754,.T.);
#756=ADVANCED_FACE('F785',(#755),#744,.F.);
#757=CARTESIAN_POINT('',(-54.6647300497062,-28.0965949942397,12.7));
#758=DIRECTION('',(-0.500000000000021,0.866025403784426,0.));
#759=DIRECTION('',(-0.866025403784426,-0.500000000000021,0.));
#760=AXIS2_PLACEMENT_3D('',#757,#758,#759);
#761=PLANE('',#760);
#762=ORIENTED_EDGE('',*,*,#467,.F.);
#763=DIRECTION('',(0.,0.,-1.));
#764=VECTOR('',#763,1.);
#765=CARTESIAN_POINT('',(-54.6647300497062,-28.0965949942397,12.7));
#766=LINE('',#765,#764);
#767=EDGE_CURVE('E401',#164,#460,#766,.T.);
#768=ORIENTED_EDGE('',*,*,#767,.F.);
#769=ORIENTED_EDGE('',*,*,#165,.T.);
#770=ORIENTED_EDGE('',*,*,#750,.T.);
#771=EDGE_LOOP('',(#762,#768,#769,#770));
#772=FACE_BOUND('',#771,.T.);
#773=ADVANCED_FACE('F716',(#772),#761,.T.);
#774=CARTESIAN_POINT('',(-55.6647300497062,-26.3645441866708,12.7));
#775=DIRECTION('',(0.,0.,-1.));
#776=DIRECTION('',(-1.,0.,0.));
#777=AXIS2_PLACEMENT_3D('',#774,#775,#776);
#778=CYLINDRICAL_SURFACE('',#777,2.);
#779=ORIENTED_EDGE('',*,*,#461,.F.);
#780=DIRECTION('',(0.,0.,-1.));
#781=VECTOR('',#780,1.);
#782=CARTESIAN_POINT('',(-56.9457197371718,-27.9004691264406,12.7));
#783=LINE('',#782,#781);
#784=EDGE_CURVE('E403',#173,#451,#783,.T.);
#785=ORIENTED_EDGE('',*,*,#784,.F.);
#786=ORIENTED_EDGE('',*,*,#174,.T.);
#787=ORIENTED_EDGE('',*,*,#767,.T.);
#788=EDGE_LOOP('',(#779,#785,#786,#787));
#789=FACE_BOUND('',#788,.T.);
#790=ADVANCED_FACE('F707',(#789),#778,.F.);
#791=CARTESIAN_POINT('',(-64.951905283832,-37.5000000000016,12.7));
#792=DIRECTION('',(0.,0.,-1.));
#793=DIRECTION('',(-1.,0.,0.));
#794=AXIS2_PLACEMENT_3D('',#791,#792,#793);
#795=CYLINDRICAL_SURFACE('',#794,12.5);
#796=CARTESIAN_POINT('',(-64.951905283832,-37.5000000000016,-10.));
#797=DIRECTION('',(0.,0.,-1.));
#798=DIRECTION('',(-1.,0.,0.));
#799=AXIS2_PLACEMENT_3D('',#796,#797,#798);
#800=CIRCLE('',#799,12.5);
#801=CARTESIAN_POINT('',(-77.451905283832,-37.5000000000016,-10.));
#802=VERTEX_POINT('',#801);
#803=EDGE_CURVE('E352',#802,#802,#800,.T.);
#804=ORIENTED_EDGE('',*,*,#803,.F.);
#805=EDGE_LOOP('',(#804));
#806=FACE_BOUND('',#805,.T.);
#807=ORIENTED_EDGE('',*,*,#452,.T.);
#808=DIRECTION('',(0.,0.,-1.));
#809=VECTOR('',#808,1.);
#810=CARTESIAN_POINT('',(-52.6353749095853,-35.3662053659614,12.7));
#811=LINE('',#810,#809);
#812=EDGE_CURVE('E406',#182,#442,#811,.T.);
#813=ORIENTED_EDGE('',*,*,#812,.F.);
#814=ORIENTED_EDGE('',*,*,#183,.F.);
#815=ORIENTED_EDGE('',*,*,#784,.T.);
#816=EDGE_LOOP('',(#807,#813,#814,#815));
#817=FACE_BOUND('',#816,.T.);
#818=ADVANCED_FACE('F704',(#806,#817),#795,.T.);
#819=CARTESIAN_POINT('',(-50.6647300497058,-35.024798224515,12.7));
#820=DIRECTION('',(0.,0.,-1.));
#821=DIRECTION('',(-1.,0.,0.));
#822=AXIS2_PLACEMENT_3D('',#819,#820,#821);
#823=CYLINDRICAL_SURFACE('',#822,2.);
#824=ORIENTED_EDGE('',*,*,#443,.T.);
#825=DIRECTION('',(0.,0.,-1.));
#826=VECTOR('',#825,1.);
#827=CARTESIAN_POINT('',(-51.6647300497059,-33.2927474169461,12.7));
#828=LINE('',#827,#826);
#829=EDGE_CURVE('E409',#191,#433,#828,.T.);
#830=ORIENTED_EDGE('',*,*,#829,.F.);
#831=ORIENTED_EDGE('',*,*,#192,.F.);
#832=ORIENTED_EDGE('',*,*,#812,.T.);
#833=EDGE_LOOP('',(#824,#830,#831,#832));
#834=FACE_BOUND('',#833,.T.);
#835=ADVANCED_FACE('F706',(#834),#823,.F.);
#836=CARTESIAN_POINT('',(-51.6647300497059,-33.2927474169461,12.7));
#837=DIRECTION('',(-0.500000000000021,0.866025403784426,0.));
#838=DIRECTION('',(-0.866025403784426,-0.500000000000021,0.));
#839=AXIS2_PLACEMENT_3D('',#836,#837,#838);
#840=PLANE('',#839);
#841=ORIENTED_EDGE('',*,*,#434,.T.);
#842=DIRECTION('',(0.,0.,-1.));
#843=VECTOR('',#842,1.);
#844=CARTESIAN_POINT('',(-14.8229133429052,-12.0221146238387,12.7));
#845=LINE('',#844,#843);
#846=EDGE_CURVE('E412',#199,#425,#845,.T.);
#847=ORIENTED_EDGE('',*,*,#846,.F.);
#848=ORIENTED_EDGE('',*,*,#200,.F.);
#849=ORIENTED_EDGE('',*,*,#829,.T.);
#850=EDGE_LOOP('',(#841,#847,#848,#849));
#851=FACE_BOUND('',#850,.T.);
#852=ADVANCED_FACE('F713',(#851),#840,.F.);
#853=CARTESIAN_POINT('',(-13.8229133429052,-13.7541654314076,12.7));
#854=DIRECTION('',(0.,0.,-1.));
#855=DIRECTION('',(-1.,0.,0.));
#856=AXIS2_PLACEMENT_3D('',#853,#854,#855);
#857=CYLINDRICAL_SURFACE('',#856,1.99999999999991);
#858=ORIENTED_EDGE('',*,*,#426,.T.);
#859=ORIENTED_EDGE('',*,*,#648,.F.);
#860=ORIENTED_EDGE('',*,*,#209,.F.);
#861=ORIENTED_EDGE('',*,*,#846,.T.);
#862=EDGE_LOOP('',(#858,#859,#860,#861));
#863=FACE_BOUND('',#862,.T.);
#864=ADVANCED_FACE('F723',(#863),#857,.F.);
#865=CARTESIAN_POINT('',(13.8229133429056,-13.7541654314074,12.7));
#866=DIRECTION('',(0.,0.,-1.));
#867=DIRECTION('',(-1.,0.,0.));
#868=AXIS2_PLACEMENT_3D('',#865,#866,#867);
#869=CYLINDRICAL_SURFACE('',#868,2.);
#870=ORIENTED_EDGE('',*,*,#408,.T.);
#871=DIRECTION('',(0.,0.,-1.));
#872=VECTOR('',#871,1.);
#873=CARTESIAN_POINT('',(14.8229133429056,-12.0221146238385,12.7));
#874=LINE('',#873,#872);
#875=CARTESIAN_POINT('',(14.8229133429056,-12.0221146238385,12.7));
#876=VERTEX_POINT('',#875);
#877=EDGE_CURVE('E416',#876,#398,#874,.T.);
#878=ORIENTED_EDGE('',*,*,#877,.F.);
#879=CARTESIAN_POINT('',(13.8229133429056,-13.7541654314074,12.7));
#880=DIRECTION('',(0.,0.,-1.));
#881=DIRECTION('',(-1.,0.,0.));
#882=AXIS2_PLACEMENT_3D('',#879,#880,#881);
#883=CIRCLE('',#882,2.);
#884=EDGE_CURVE('E457',#656,#876,#883,.T.);
#885=ORIENTED_EDGE('',*,*,#884,.F.);
#886=ORIENTED_EDGE('',*,*,#657,.T.);
#887=EDGE_LOOP('',(#870,#878,#885,#886));
#888=FACE_BOUND('',#887,.T.);
#889=ADVANCED_FACE('F727',(#888),#869,.F.);
#890=CARTESIAN_POINT('',(14.8229133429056,-12.0221146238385,12.7));
#891=DIRECTION('',(0.499999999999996,0.866025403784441,0.));
#892=DIRECTION('',(-0.866025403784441,0.499999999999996,0.));
#893=AXIS2_PLACEMENT_3D('',#890,#891,#892);
#894=PLANE('',#893);
#895=ORIENTED_EDGE('',*,*,#399,.T.);
#896=DIRECTION('',(0.,0.,-1.));
#897=VECTOR('',#896,1.);
#898=CARTESIAN_POINT('',(51.6647300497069,-33.2927474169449,12.7));
#899=LINE('',#898,#897);
#900=CARTESIAN_POINT('',(51.6647300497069,-33.2927474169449,12.7));
#901=VERTEX_POINT('',#900);
#902=EDGE_CURVE('E420',#901,#390,#899,.T.);
#903=ORIENTED_EDGE('',*,*,#902,.F.);
#904=DIRECTION('',(0.866025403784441,-0.499999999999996,0.));
#905=VECTOR('',#904,1.);
#906=CARTESIAN_POINT('',(14.8229133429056,-12.0221146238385,12.7));
#907=LINE('',#906,#905);
#908=EDGE_CURVE('E455',#876,#901,#907,.T.);
#909=ORIENTED_EDGE('',*,*,#908,.F.);
#910=ORIENTED_EDGE('',*,*,#877,.T.);
#911=EDGE_LOOP('',(#895,#903,#909,#910));
#912=FACE_BOUND('',#911,.T.);
#913=ADVANCED_FACE('F731',(#912),#894,.F.);
#914=CARTESIAN_POINT('',(50.6647300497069,-35.0247982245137,12.7));
#915=DIRECTION('',(0.,0.,-1.));
#916=DIRECTION('',(-1.,0.,0.));
#917=AXIS2_PLACEMENT_3D('',#914,#915,#916);
#918=CYLINDRICAL_SURFACE('',#917,1.99999999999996);
#919=ORIENTED_EDGE('',*,*,#391,.F.);
#920=DIRECTION('',(0.,0.,-1.));
#921=VECTOR('',#920,1.);
#922=CARTESIAN_POINT('',(52.6353749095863,-35.3662053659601,12.7));
#923=LINE('',#922,#921);
#924=CARTESIAN_POINT('',(52.6353749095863,-35.3662053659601,12.7));
#925=VERTEX_POINT('',#924);
#926=EDGE_CURVE('E422',#925,#381,#923,.T.);
#927=ORIENTED_EDGE('',*,*,#926,.F.);
#928=CARTESIAN_POINT('',(50.6647300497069,-35.0247982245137,12.7));
#929=DIRECTION('',(0.,0.,1.));
#930=DIRECTION('',(1.,0.,0.));
#931=AXIS2_PLACEMENT_3D('',#928,#929,#930);
#932=CIRCLE('',#931,1.99999999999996);
#933=EDGE_CURVE('E452',#925,#901,#932,.T.);
#934=ORIENTED_EDGE('',*,*,#933,.T.);
#935=ORIENTED_EDGE('',*,*,#902,.T.);
#936=EDGE_LOOP('',(#919,#927,#934,#935));
#937=FACE_BOUND('',#936,.T.);
#938=ADVANCED_FACE('F735',(#937),#918,.F.);
#939=CARTESIAN_POINT('',(64.9519052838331,-37.4999999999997,12.7));
#940=DIRECTION('',(0.,0.,-1.));
#941=DIRECTION('',(-1.,0.,0.));
#942=AXIS2_PLACEMENT_3D('',#939,#940,#941);
#943=CYLINDRICAL_SURFACE('',#942,12.5);
#944=CARTESIAN_POINT('',(64.9519052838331,-37.4999999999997,-10.));
#945=DIRECTION('',(0.,0.,-1.));
#946=DIRECTION('',(-1.,0.,0.));
#947=AXIS2_PLACEMENT_3D('',#944,#945,#946);
#948=CIRCLE('',#947,12.5);
#949=CARTESIAN_POINT('',(52.4519052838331,-37.4999999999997,-10.));
#950=VERTEX_POINT('',#949);
#951=EDGE_CURVE('E441',#950,#950,#948,.T.);
#952=ORIENTED_EDGE('',*,*,#951,.F.);
#953=EDGE_LOOP('',(#952));
#954=FACE_BOUND('',#953,.T.);
#955=ORIENTED_EDGE('',*,*,#382,.T.);
#956=DIRECTION('',(0.,0.,-1.));
#957=VECTOR('',#956,1.);
#958=CARTESIAN_POINT('',(56.9457197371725,-27.9004691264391,12.7));
#959=LINE('',#958,#957);
#960=CARTESIAN_POINT('',(56.9457197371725,-27.9004691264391,12.7));
#961=VERTEX_POINT('',#960);
#962=EDGE_CURVE('E425',#961,#372,#959,.T.);
#963=ORIENTED_EDGE('',*,*,#962,.F.);
#964=CARTESIAN_POINT('',(64.9519052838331,-37.4999999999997,12.7));
#965=DIRECTION('',(0.,0.,1.));
#966=DIRECTION('',(1.,0.,0.));
#967=AXIS2_PLACEMENT_3D('',#964,#965,#966);
#968=CIRCLE('',#967,12.5);
#969=EDGE_CURVE('E450',#925,#961,#968,.T.);
#970=ORIENTED_EDGE('',*,*,#969,.F.);
#971=ORIENTED_EDGE('',*,*,#926,.T.);
#972=EDGE_LOOP('',(#955,#963,#970,#971));
#973=FACE_BOUND('',#972,.T.);
#974=ADVANCED_FACE('F739',(#954,#973),#943,.T.);
#975=CARTESIAN_POINT('',(55.6647300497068,-26.3645441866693,12.7));
#976=DIRECTION('',(0.,0.,-1.));
#977=DIRECTION('',(-1.,0.,0.));
#978=AXIS2_PLACEMENT_3D('',#975,#976,#977);
#979=CYLINDRICAL_SURFACE('',#978,2.00000000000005);
#980=ORIENTED_EDGE('',*,*,#373,.F.);
#981=DIRECTION('',(0.,0.,-1.));
#982=VECTOR('',#981,1.);
#983=CARTESIAN_POINT('',(54.6647300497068,-28.0965949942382,12.7));
#984=LINE('',#983,#982);
#985=CARTESIAN_POINT('',(54.6647300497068,-28.0965949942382,12.7));
#986=VERTEX_POINT('',#985);
#987=EDGE_CURVE('E428',#986,#363,#984,.T.);
#988=ORIENTED_EDGE('',*,*,#987,.F.);
#989=CARTESIAN_POINT('',(55.6647300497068,-26.3645441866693,12.7));
#990=DIRECTION('',(0.,0.,1.));
#991=DIRECTION('',(1.,0.,0.));
#992=AXIS2_PLACEMENT_3D('',#989,#990,#991);
#993=CIRCLE('',#992,2.00000000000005);
#994=EDGE_CURVE('E446',#986,#961,#993,.T.);
#995=ORIENTED_EDGE('',*,*,#994,.T.);
#996=ORIENTED_EDGE('',*,*,#962,.T.);
#997=EDGE_LOOP('',(#980,#988,#995,#996));
#998=FACE_BOUND('',#997,.T.);
#999=ADVANCED_FACE('F743',(#998),#979,.F.);
#1000=CARTESIAN_POINT('',(17.8229133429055,-6.82596220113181,12.7));
#1001=DIRECTION('',(0.499999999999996,0.866025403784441,0.));
#1002=DIRECTION('',(-0.866025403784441,0.499999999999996,0.));
#1003=AXIS2_PLACEMENT_3D('',#1000,#1001,#1002);
#1004=PLANE('',#1003);
#1005=ORIENTED_EDGE('',*,*,#364,.F.);
#1006=DIRECTION('',(0.,0.,-1.));
#1007=VECTOR('',#1006,1.);
#1008=CARTESIAN_POINT('',(17.8229133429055,-6.82596220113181,12.7));
#1009=LINE('',#1008,#1007);
#1010=CARTESIAN_POINT('',(17.8229133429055,-6.82596220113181,12.7));
#1011=VERTEX_POINT('',#1010);
#1012=EDGE_CURVE('E430',#1011,#355,#1009,.T.);
#1013=ORIENTED_EDGE('',*,*,#1012,.F.);
#1014=DIRECTION('',(0.866025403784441,-0.499999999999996,0.));
#1015=VECTOR('',#1014,1.);
#1016=CARTESIAN_POINT('',(17.8229133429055,-6.82596220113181,12.7));
#1017=LINE('',#1016,#1015);
#1018=EDGE_CURVE('E443',#1011,#986,#1017,.T.);
#1019=ORIENTED_EDGE('',*,*,#1018,.T.);
#1020=ORIENTED_EDGE('',*,*,#987,.T.);
#1021=EDGE_LOOP('',(#1005,#1013,#1019,#1020));
#1022=FACE_BOUND('',#1021,.T.);
#1023=ADVANCED_FACE('F641',(#1022),#1004,.T.);
#1024=CARTESIAN_POINT('',(18.8229133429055,-5.09391139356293,12.7));
#1025=DIRECTION('',(0.,0.,-1.));
#1026=DIRECTION('',(-1.,0.,0.));
#1027=AXIS2_PLACEMENT_3D('',#1024,#1025,#1026);
#1028=CYLINDRICAL_SURFACE('',#1027,2.);
#1029=ORIENTED_EDGE('',*,*,#356,.F.);
#1030=ORIENTED_EDGE('',*,*,#696,.F.);
#1031=CARTESIAN_POINT('',(18.8229133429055,-5.09391139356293,12.7));
#1032=DIRECTION('',(0.,0.,1.));
#1033=DIRECTION('',(1.,0.,0.));
#1034=AXIS2_PLACEMENT_3D('',#1031,#1032,#1033);
#1035=CIRCLE('',#1034,2.);
#1036=EDGE_CURVE('E447',#689,#1011,#1035,.T.);
#1037=ORIENTED_EDGE('',*,*,#1036,.T.);
#1038=ORIENTED_EDGE('',*,*,#1012,.T.);
#1039=EDGE_LOOP('',(#1029,#1030,#1037,#1038));
#1040=FACE_BOUND('',#1039,.T.);
#1041=ADVANCED_FACE('F634',(#1040),#1028,.F.);
#1042=DIRECTION('',(0.866025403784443,-0.499999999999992,0.));
#1043=VECTOR('',#1042,1.);
#1044=CARTESIAN_POINT('',(-4.91145667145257,1.68093029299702,12.7));
#1045=LINE('',#1044,#1043);
#1046=CARTESIAN_POINT('',(45.1600466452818,-27.2278656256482,12.7));
#1047=VERTEX_POINT('',#1046);
#1048=EDGE_CURVE('E255',#660,#1047,#1045,.T.);
#1049=ORIENTED_EDGE('',*,*,#1048,.F.);
#1050=ORIENTED_EDGE('',*,*,#661,.F.);
#1051=ORIENTED_EDGE('',*,*,#884,.T.);
#1052=ORIENTED_EDGE('',*,*,#908,.T.);
#1053=ORIENTED_EDGE('',*,*,#933,.F.);
#1054=ORIENTED_EDGE('',*,*,#969,.T.);
#1055=ORIENTED_EDGE('',*,*,#994,.F.);
#1056=ORIENTED_EDGE('',*,*,#1018,.F.);
#1057=ORIENTED_EDGE('',*,*,#1036,.F.);
#1058=ORIENTED_EDGE('',*,*,#690,.F.);
#1059=DIRECTION('',(0.866025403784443,-0.499999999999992,0.));
#1060=VECTOR('',#1059,1.);
#1061=CARTESIAN_POINT('',(-3.91145667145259,3.41298110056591,12.7));
#1062=LINE('',#1061,#1060);
#1063=CARTESIAN_POINT('',(46.1600466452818,-25.4958148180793,12.7));
#1064=VERTEX_POINT('',#1063);
#1065=EDGE_CURVE('E251',#685,#1064,#1062,.T.);
#1066=ORIENTED_EDGE('',*,*,#1065,.T.);
#1067=DIRECTION('',(0.499999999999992,0.866025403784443,0.));
#1068=VECTOR('',#1067,1.);
#1069=CARTESIAN_POINT('',(55.0715033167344,-10.0607190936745,12.7));
#1070=LINE('',#1069,#1068);
#1071=EDGE_CURVE('E263',#1047,#1064,#1070,.T.);
#1072=ORIENTED_EDGE('',*,*,#1071,.F.);
#1073=EDGE_LOOP('',(#1049,#1050,#1051,#1052,#1053,#1054,#1055,#1056,#1057,#1058,#1066,#1072));
#1074=FACE_BOUND('',#1073,.T.);
#1075=CARTESIAN_POINT('',(64.9519052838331,-37.4999999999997,12.7));
#1076=DIRECTION('',(0.,0.,1.));
#1077=DIRECTION('',(1.,0.,0.));
#1078=AXIS2_PLACEMENT_3D('',#1075,#1076,#1077);
#1079=CIRCLE('',#1078,7.5);
#1080=CARTESIAN_POINT('',(72.4519052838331,-37.4999999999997,12.7));
#1081=VERTEX_POINT('',#1080);
#1082=EDGE_CURVE('E314',#1081,#1081,#1079,.T.);
#1083=ORIENTED_EDGE('',*,*,#1082,.F.);
#1084=EDGE_LOOP('',(#1083));
#1085=FACE_BOUND('',#1084,.T.);
#1086=ADVANCED_FACE('F626',(#1074,#1085),#23,.T.);
#1087=CARTESIAN_POINT('',(0.,75.,-10.));
#1088=DIRECTION('',(0.,0.,-1.));
#1089=DIRECTION('',(-1.,0.,0.));
#1090=AXIS2_PLACEMENT_3D('',#1087,#1088,#1089);
#1091=PLANE('',#1090);
#1092=CARTESIAN_POINT('',(0.,75.,-10.));
#1093=DIRECTION('',(0.,0.,1.));
#1094=DIRECTION('',(1.,0.,0.));
#1095=AXIS2_PLACEMENT_3D('',#1092,#1093,#1094);
#1096=CIRCLE('',#1095,7.5);
#1097=CARTESIAN_POINT('',(7.5,75.,-10.));
#1098=VERTEX_POINT('',#1097);
#1099=EDGE_CURVE('E327',#1098,#1098,#1096,.T.);
#1100=ORIENTED_EDGE('',*,*,#1099,.T.);
#1101=EDGE_LOOP('',(#1100));
#1102=FACE_BOUND('',#1101,.T.);
#1103=ORIENTED_EDGE('',*,*,#540,.T.);
#1104=EDGE_LOOP('',(#1103));
#1105=FACE_BOUND('',#1104,.T.);
#1106=ADVANCED_FACE('F633',(#1102,#1105),#1091,.T.);
#1107=CARTESIAN_POINT('',(64.9519052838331,-37.4999999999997,-10.));
#1108=DIRECTION('',(0.,0.,-1.));
#1109=DIRECTION('',(-1.,0.,0.));
#1110=AXIS2_PLACEMENT_3D('',#1107,#1108,#1109);
#1111=PLANE('',#1110);
#1112=CARTESIAN_POINT('',(64.9519052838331,-37.4999999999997,-10.));
#1113=DIRECTION('',(0.,0.,1.));
#1114=DIRECTION('',(1.,0.,0.));
#1115=AXIS2_PLACEMENT_3D('',#1112,#1113,#1114);
#1116=CIRCLE('',#1115,7.5);
#1117=CARTESIAN_POINT('',(72.4519052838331,-37.4999999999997,-10.));
#1118=VERTEX_POINT('',#1117);
#1119=EDGE_CURVE('E315',#1118,#1118,#1116,.T.);
#1120=ORIENTED_EDGE('',*,*,#1119,.T.);
#1121=EDGE_LOOP('',(#1120));
#1122=FACE_BOUND('',#1121,.T.);
#1123=ORIENTED_EDGE('',*,*,#951,.T.);
#1124=EDGE_LOOP('',(#1123));
#1125=FACE_BOUND('',#1124,.T.);
#1126=ADVANCED_FACE('F639',(#1122,#1125),#1111,.T.);
#1127=CARTESIAN_POINT('',(-64.951905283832,-37.5000000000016,-10.));
#1128=DIRECTION('',(0.,0.,-1.));
#1129=DIRECTION('',(-1.,0.,0.));
#1130=AXIS2_PLACEMENT_3D('',#1127,#1128,#1129);
#1131=PLANE('',#1130);
#1132=CARTESIAN_POINT('',(-64.951905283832,-37.5000000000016,-10.));
#1133=DIRECTION('',(0.,0.,1.));
#1134=DIRECTION('',(1.,0.,0.));
#1135=AXIS2_PLACEMENT_3D('',#1132,#1133,#1134);
#1136=CIRCLE('',#1135,7.5);
#1137=CARTESIAN_POINT('',(-57.451905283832,-37.5000000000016,-10.));
#1138=VERTEX_POINT('',#1137);
#1139=EDGE_CURVE('E321',#1138,#1138,#1136,.T.);
#1140=ORIENTED_EDGE('',*,*,#1139,.T.);
#1141=EDGE_LOOP('',(#1140));
#1142=FACE_BOUND('',#1141,.T.);
#1143=ORIENTED_EDGE('',*,*,#803,.T.);
#1144=EDGE_LOOP('',(#1143));
#1145=FACE_BOUND('',#1144,.T.);
#1146=ADVANCED_FACE('F683',(#1142,#1145),#1131,.T.);
#1147=CARTESIAN_POINT('',(0.,0.,32.7));
#1148=DIRECTION('',(0.,0.,1.));
#1149=DIRECTION('',(1.,0.,0.));
#1150=AXIS2_PLACEMENT_3D('',#1147,#1148,#1149);
#1151=PLANE('',#1150);
#1152=CARTESIAN_POINT('',(0.,0.,32.7));
#1153=DIRECTION('',(0.,0.,1.));
#1154=DIRECTION('',(1.,0.,0.));
#1155=AXIS2_PLACEMENT_3D('',#1152,#1153,#1154);
#1156=CIRCLE('',#1155,13.9874670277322);
#1157=CARTESIAN_POINT('',(13.9874670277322,0.,32.7));
#1158=VERTEX_POINT('',#1157);
#1159=EDGE_CURVE('E338',#1158,#1158,#1156,.T.);
#1160=ORIENTED_EDGE('',*,*,#1159,.F.);
#1161=EDGE_LOOP('',(#1160));
#1162=FACE_BOUND('',#1161,.T.);
#1163=ORIENTED_EDGE('',*,*,#735,.T.);
#1164=EDGE_LOOP('',(#1163));
#1165=FACE_BOUND('',#1164,.T.);
#1166=ADVANCED_FACE('F679',(#1162,#1165),#1151,.T.);
#1167=CARTESIAN_POINT('',(0.,0.,12.7));
#1168=DIRECTION('',(0.,0.,1.));
#1169=DIRECTION('',(1.,0.,0.));
#1170=AXIS2_PLACEMENT_3D('',#1167,#1168,#1169);
#1171=CYLINDRICAL_SURFACE('',#1170,13.9874670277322);
#1172=CARTESIAN_POINT('',(0.,0.,12.7));
#1173=DIRECTION('',(0.,0.,1.));
#1174=DIRECTION('',(1.,0.,0.));
#1175=AXIS2_PLACEMENT_3D('',#1172,#1173,#1174);
#1176=CIRCLE('',#1175,13.9874670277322);
#1177=CARTESIAN_POINT('',(13.9874670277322,0.,12.7));
#1178=VERTEX_POINT('',#1177);
#1179=EDGE_CURVE('E339',#1178,#1178,#1176,.T.);
#1180=ORIENTED_EDGE('',*,*,#1179,.F.);
#1181=EDGE_LOOP('',(#1180));
#1182=FACE_BOUND('',#1181,.T.);
#1183=ORIENTED_EDGE('',*,*,#1159,.T.);
#1184=EDGE_LOOP('',(#1183));
#1185=FACE_BOUND('',#1184,.T.);
#1186=ADVANCED_FACE('F675',(#1182,#1185),#1171,.F.);
#1187=CARTESIAN_POINT('',(0.,0.,12.7));
#1188=DIRECTION('',(0.,0.,1.));
#1189=DIRECTION('',(1.,0.,0.));
#1190=AXIS2_PLACEMENT_3D('',#1187,#1188,#1189);
#1191=PLANE('',#1190);
#1192=CARTESIAN_POINT('',(0.,0.,12.7));
#1193=DIRECTION('',(0.,0.,1.));
#1194=DIRECTION('',(1.,0.,0.));
#1195=AXIS2_PLACEMENT_3D('',#1192,#1193,#1194);
#1196=CIRCLE('',#1195,8.33292396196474);
#1197=CARTESIAN_POINT('',(8.33292396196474,0.,12.7));
#1198=VERTEX_POINT('',#1197);
#1199=EDGE_CURVE('E330',#1198,#1198,#1196,.T.);
#1200=ORIENTED_EDGE('',*,*,#1199,.F.);
#1201=EDGE_LOOP('',(#1200));
#1202=FACE_BOUND('',#1201,.T.);
#1203=ORIENTED_EDGE('',*,*,#1179,.T.);
#1204=EDGE_LOOP('',(#1203));
#1205=FACE_BOUND('',#1204,.T.);
#1206=ADVANCED_FACE('F671',(#1202,#1205),#1191,.T.);
#1207=CARTESIAN_POINT('',(0.,0.,-10.));
#1208=DIRECTION('',(0.,0.,1.));
#1209=DIRECTION('',(1.,0.,0.));
#1210=AXIS2_PLACEMENT_3D('',#1207,#1208,#1209);
#1211=CYLINDRICAL_SURFACE('',#1210,8.33292396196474);
#1212=ORIENTED_EDGE('',*,*,#255,.F.);
#1213=EDGE_LOOP('',(#1212));
#1214=FACE_BOUND('',#1213,.T.);
#1215=ORIENTED_EDGE('',*,*,#1199,.T.);
#1216=EDGE_LOOP('',(#1215));
#1217=FACE_BOUND('',#1216,.T.);
#1218=ADVANCED_FACE('F667',(#1214,#1217),#1211,.F.);
#1219=CARTESIAN_POINT('',(0.,75.,-10.));
#1220=DIRECTION('',(0.,0.,1.));
#1221=DIRECTION('',(1.,0.,0.));
#1222=AXIS2_PLACEMENT_3D('',#1219,#1220,#1221);
#1223=CYLINDRICAL_SURFACE('',#1222,7.5);
#1224=ORIENTED_EDGE('',*,*,#1099,.F.);
#1225=EDGE_LOOP('',(#1224));
#1226=FACE_BOUND('',#1225,.T.);
#1227=ORIENTED_EDGE('',*,*,#131,.T.);
#1228=EDGE_LOOP('',(#1227));
#1229=FACE_BOUND('',#1228,.T.);
#1230=ADVANCED_FACE('F659',(#1226,#1229),#1223,.F.);
#1231=CARTESIAN_POINT('',(-64.951905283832,-37.5000000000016,-10.));
#1232=DIRECTION('',(0.,0.,1.));
#1233=DIRECTION('',(1.,0.,0.));
#1234=AXIS2_PLACEMENT_3D('',#1231,#1232,#1233);
#1235=CYLINDRICAL_SURFACE('',#1234,7.5);
#1236=ORIENTED_EDGE('',*,*,#1139,.F.);
#1237=EDGE_LOOP('',(#1236));
#1238=FACE_BOUND('',#1237,.T.);
#1239=ORIENTED_EDGE('',*,*,#238,.T.);
#1240=EDGE_LOOP('',(#1239));
#1241=FACE_BOUND('',#1240,.T.);
#1242=ADVANCED_FACE('F649',(#1238,#1241),#1235,.F.);
#1243=CARTESIAN_POINT('',(64.9519052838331,-37.4999999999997,-10.));
#1244=DIRECTION('',(0.,0.,1.));
#1245=DIRECTION('',(1.,0.,0.));
#1246=AXIS2_PLACEMENT_3D('',#1243,#1244,#1245);
#1247=CYLINDRICAL_SURFACE('',#1246,7.5);
#1248=ORIENTED_EDGE('',*,*,#1119,.F.);
#1249=EDGE_LOOP('',(#1248));
#1250=FACE_BOUND('',#1249,.T.);
#1251=ORIENTED_EDGE('',*,*,#1082,.T.);
#1252=EDGE_LOOP('',(#1251));
#1253=FACE_BOUND('',#1252,.T.);
#1254=ADVANCED_FACE('F646',(#1250,#1253),#1247,.F.);
#1255=CARTESIAN_POINT('',(0.,58.8057721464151,10.0098440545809));
#1256=DIRECTION('',(0.,0.404506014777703,0.914535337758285));
#1257=DIRECTION('',(0.,-0.914535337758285,0.404506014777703));
#1258=AXIS2_PLACEMENT_3D('',#1255,#1256,#1257);
#1259=PLANE('',#1258);
#1260=DIRECTION('',(0.,-0.914535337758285,0.404506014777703));
#1261=VECTOR('',#1260,1.);
#1262=CARTESIAN_POINT('',(1.,58.8057721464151,10.0098440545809));
#1263=LINE('',#1262,#1261);
#1264=EDGE_CURVE('E294',#31,#706,#1263,.T.);
#1265=ORIENTED_EDGE('',*,*,#1264,.F.);
#1266=ORIENTED_EDGE('',*,*,#120,.T.);
#1267=DIRECTION('',(0.,-0.914535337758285,0.404506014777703));
#1268=VECTOR('',#1267,1.);
#1269=CARTESIAN_POINT('',(-1.,58.8057721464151,10.0098440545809));
#1270=LINE('',#1269,#1268);
#1271=EDGE_CURVE('E293',#113,#715,#1270,.T.);
#1272=ORIENTED_EDGE('',*,*,#1271,.T.);
#1273=ORIENTED_EDGE('',*,*,#716,.F.);
#1274=EDGE_LOOP('',(#1265,#1266,#1272,#1273));
#1275=FACE_BOUND('',#1274,.T.);
#1276=ADVANCED_FACE('F648',(#1275),#1259,.T.);
#1277=CARTESIAN_POINT('',(1.,18.7499999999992,11.35));
#1278=DIRECTION('',(1.,0.,0.));
#1279=DIRECTION('',(0.,0.,-1.));
#1280=AXIS2_PLACEMENT_3D('',#1277,#1278,#1279);
#1281=PLANE('',#1280);
#1282=ORIENTED_EDGE('',*,*,#707,.F.);
#1283=ORIENTED_EDGE('',*,*,#32,.T.);
#1284=ORIENTED_EDGE('',*,*,#1264,.T.);
#1285=EDGE_LOOP('',(#1282,#1283,#1284));
#1286=FACE_BOUND('',#1285,.T.);
#1287=ADVANCED_FACE('F656',(#1286),#1281,.T.);
#1288=CARTESIAN_POINT('',(-1.,18.7499999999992,11.35));
#1289=DIRECTION('',(1.,0.,0.));
#1290=DIRECTION('',(0.,0.,-1.));
#1291=AXIS2_PLACEMENT_3D('',#1288,#1289,#1290);
#1292=PLANE('',#1291);
#1293=ORIENTED_EDGE('',*,*,#114,.F.);
#1294=ORIENTED_EDGE('',*,*,#722,.T.);
#1295=ORIENTED_EDGE('',*,*,#1271,.F.);
#1296=EDGE_LOOP('',(#1293,#1294,#1295));
#1297=FACE_BOUND('',#1296,.T.);
#1298=ADVANCED_FACE('F791',(#1297),#1292,.F.);
#1299=CARTESIAN_POINT('',(-50.9272925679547,-29.4028860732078,10.0098440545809));
#1300=DIRECTION('',(-0.350312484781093,-0.202253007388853,0.914535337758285));
#1301=DIRECTION('',(0.792010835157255,0.457267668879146,0.404506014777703));
#1302=AXIS2_PLACEMENT_3D('',#1299,#1300,#1301);
#1303=PLANE('',#1302);
#1304=DIRECTION('',(0.792010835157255,0.457267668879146,0.404506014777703));
#1305=VECTOR('',#1304,1.);
#1306=CARTESIAN_POINT('',(-51.4272925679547,-28.5368606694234,10.0098440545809));
#1307=LINE('',#1306,#1305);
#1308=EDGE_CURVE('E274',#143,#625,#1307,.T.);
#1309=ORIENTED_EDGE('',*,*,#1308,.F.);
#1310=ORIENTED_EDGE('',*,*,#227,.T.);
#1311=DIRECTION('',(0.792010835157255,0.457267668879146,0.404506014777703));
#1312=VECTOR('',#1311,1.);
#1313=CARTESIAN_POINT('',(-50.4272925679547,-30.2689114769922,10.0098440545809));
#1314=LINE('',#1313,#1312);
#1315=EDGE_CURVE('E271',#220,#634,#1314,.T.);
#1316=ORIENTED_EDGE('',*,*,#1315,.T.);
#1317=ORIENTED_EDGE('',*,*,#635,.F.);
#1318=EDGE_LOOP('',(#1309,#1310,#1316,#1317));
#1319=FACE_BOUND('',#1318,.T.);
#1320=ADVANCED_FACE('F956',(#1319),#1303,.T.);
#1321=CARTESIAN_POINT('',(7.61898816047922,5.55352540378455,11.35));
#1322=DIRECTION('',(-0.500000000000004,0.866025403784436,0.));
#1323=DIRECTION('',(-0.866025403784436,-0.500000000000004,0.));
#1324=AXIS2_PLACEMENT_3D('',#1321,#1322,#1323);
#1325=PLANE('',#1324);
#1326=ORIENTED_EDGE('',*,*,#626,.F.);
#1327=ORIENTED_EDGE('',*,*,#144,.T.);
#1328=ORIENTED_EDGE('',*,*,#1308,.T.);
#1329=EDGE_LOOP('',(#1326,#1327,#1328));
#1330=FACE_BOUND('',#1329,.T.);
#1331=ADVANCED_FACE('F1028',(#1330),#1325,.T.);
#1332=CARTESIAN_POINT('',(8.61898816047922,3.82147459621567,11.35));
#1333=DIRECTION('',(-0.500000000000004,0.866025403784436,0.));
#1334=DIRECTION('',(-0.866025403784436,-0.500000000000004,0.));
#1335=AXIS2_PLACEMENT_3D('',#1332,#1333,#1334);
#1336=PLANE('',#1335);
#1337=ORIENTED_EDGE('',*,*,#221,.F.);
#1338=ORIENTED_EDGE('',*,*,#641,.T.);
#1339=ORIENTED_EDGE('',*,*,#1315,.F.);
#1340=EDGE_LOOP('',(#1337,#1338,#1339));
#1341=FACE_BOUND('',#1340,.T.);
#1342=ADVANCED_FACE('F1038',(#1341),#1336,.F.);
#1343=CARTESIAN_POINT('',(50.9272925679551,-29.4028860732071,10.0098440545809));
#1344=DIRECTION('',(0.350312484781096,-0.202253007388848,0.914535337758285));
#1345=DIRECTION('',(-0.792010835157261,0.457267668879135,0.404506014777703));
#1346=AXIS2_PLACEMENT_3D('',#1343,#1344,#1345);
#1347=PLANE('',#1346);
#1348=ORIENTED_EDGE('',*,*,#678,.F.);
#1349=DIRECTION('',(-0.792010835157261,0.457267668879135,0.404506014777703));
#1350=VECTOR('',#1349,1.);
#1351=CARTESIAN_POINT('',(50.4272925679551,-30.2689114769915,10.0098440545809));
#1352=LINE('',#1351,#1350);
#1353=EDGE_CURVE('E264',#1047,#668,#1352,.T.);
#1354=ORIENTED_EDGE('',*,*,#1353,.F.);
#1355=ORIENTED_EDGE('',*,*,#1071,.T.);
#1356=DIRECTION('',(-0.792010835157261,0.457267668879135,0.404506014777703));
#1357=VECTOR('',#1356,1.);
#1358=CARTESIAN_POINT('',(51.4272925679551,-28.5368606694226,10.0098440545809));
#1359=LINE('',#1358,#1357);
#1360=EDGE_CURVE('E50',#1064,#677,#1359,.T.);
#1361=ORIENTED_EDGE('',*,*,#1360,.T.);
#1362=EDGE_LOOP('',(#1348,#1354,#1355,#1361));
#1363=FACE_BOUND('',#1362,.T.);
#1364=ADVANCED_FACE('F258',(#1363),#1347,.T.);
#1365=CARTESIAN_POINT('',(-8.61898816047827,3.82147459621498,11.35));
#1366=DIRECTION('',(-0.499999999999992,-0.866025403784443,0.));
#1367=DIRECTION('',(0.866025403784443,-0.499999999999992,0.));
#1368=AXIS2_PLACEMENT_3D('',#1365,#1366,#1367);
#1369=PLANE('',#1368);
#1370=ORIENTED_EDGE('',*,*,#669,.F.);
#1371=ORIENTED_EDGE('',*,*,#1048,.T.);
#1372=ORIENTED_EDGE('',*,*,#1353,.T.);
#1373=EDGE_LOOP('',(#1370,#1371,#1372));
#1374=FACE_BOUND('',#1373,.T.);
#1375=ADVANCED_FACE('F1057',(#1374),#1369,.T.);
#1376=CARTESIAN_POINT('',(-7.61898816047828,5.55352540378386,11.35));
#1377=DIRECTION('',(-0.499999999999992,-0.866025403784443,0.));
#1378=DIRECTION('',(0.866025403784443,-0.499999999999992,0.));
#1379=AXIS2_PLACEMENT_3D('',#1376,#1377,#1378);
#1380=PLANE('',#1379);
#1381=ORIENTED_EDGE('',*,*,#1065,.F.);
#1382=ORIENTED_EDGE('',*,*,#686,.T.);
#1383=ORIENTED_EDGE('',*,*,#1360,.F.);
#1384=EDGE_LOOP('',(#1381,#1382,#1383));
#1385=FACE_BOUND('',#1384,.T.);
#1386=ADVANCED_FACE('F249',(#1385),#1380,.F.);
#1387=CLOSED_SHELL('',(#135,#242,#471,#493,#510,#527,#555,#572,#589,#606,#739,#756,#773,#790,
#818,#835,#852,#864,#889,#913,#938,#974,#999,#1023,#1041,#1086,#1106,#1126,#1146,#1166,#1186,
#1206,#1218,#1230,#1242,#1254,#1276,#1287,#1298,#1320,#1331,#1342,#1364,#1375,#1386));
#1388=MANIFOLD_SOLID_BREP('B2',#1387);
#1389=ADVANCED_BREP_SHAPE_REPRESENTATION('',(#18,#1388),#14);
#1390=SHAPE_DEFINITION_REPRESENTATION(#9,#1389);
ENDSEC;
END-ISO-10303-21;
